VERSION 5.7 ;
  NOWIREEXTENSIONATPIN ON ;
  DIVIDERCHAR "/" ;
  BUSBITCHARS "[]" ;
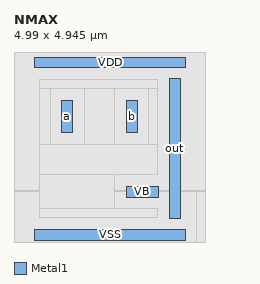
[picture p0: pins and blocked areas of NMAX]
MACRO NMAX
  CLASS core ;
  FOREIGN NMAX ;
  ORIGIN 0.545 0.190 ;
  SIZE 4.990 BY 4.945 ;
  SITE site056um ;
  PIN VSS
    DIRECTION INOUT ;
    USE GROUND ;
    PORT
      LAYER Metal1 ;
        RECT 0.000 -0.140 3.920 0.140 ;
    END
  END VSS
  PIN VDD
    DIRECTION INOUT ;
    USE POWER ;
    PORT
      LAYER Metal1 ;
        RECT 0.000 4.340 3.920 4.620 ;
    END
  END VDD
  PIN out
    DIRECTION OUTPUT ;
    USE SIGNAL ;
    ANTENNAGATEAREA 0.246400 ;
    ANTENNADIFFAREA 0.522800 ;
    PORT
      LAYER Metal1 ;
        RECT 3.500 0.420 3.780 4.060 ;
    END
  END out
  PIN VB
    DIRECTION INOUT ;
    USE POWER ;
    PORT
      LAYER Metal1 ;
        RECT 2.380 0.980 3.220 1.260 ;
    END
  END VB
  PIN a
    DIRECTION INOUT ;
    USE SIGNAL ;
    ANTENNAGATEAREA 0.453200 ;
    PORT
      LAYER Metal1 ;
        RECT 0.700 2.660 0.980 3.500 ;
    END
  END a
  PIN b
    DIRECTION INOUT ;
    USE SIGNAL ;
    ANTENNAGATEAREA 0.453200 ;
    PORT
      LAYER Metal1 ;
        RECT 2.380 2.660 2.660 3.500 ;
    END
  END b
  OBS
      LAYER Nwell ;
        RECT -0.545 1.140 4.445 4.755 ;
      LAYER Pwell ;
        RECT -0.545 1.135 0.765 1.140 ;
      LAYER Nwell ;
        RECT 0.765 1.135 4.445 1.140 ;
      LAYER Pwell ;
        RECT -0.545 -0.190 4.200 1.135 ;
      LAYER Nwell ;
        RECT 4.200 -0.190 4.445 1.135 ;
      LAYER Metal1 ;
        RECT 0.125 3.800 3.200 4.040 ;
        RECT 0.125 2.360 0.400 3.800 ;
        RECT 1.280 2.360 2.080 3.800 ;
        RECT 2.960 2.360 3.200 3.800 ;
        RECT 0.125 1.560 3.200 2.360 ;
        RECT 0.125 0.680 2.080 1.560 ;
        RECT 0.125 0.440 3.200 0.680 ;
  END
END NMAX
END LIBRARY

